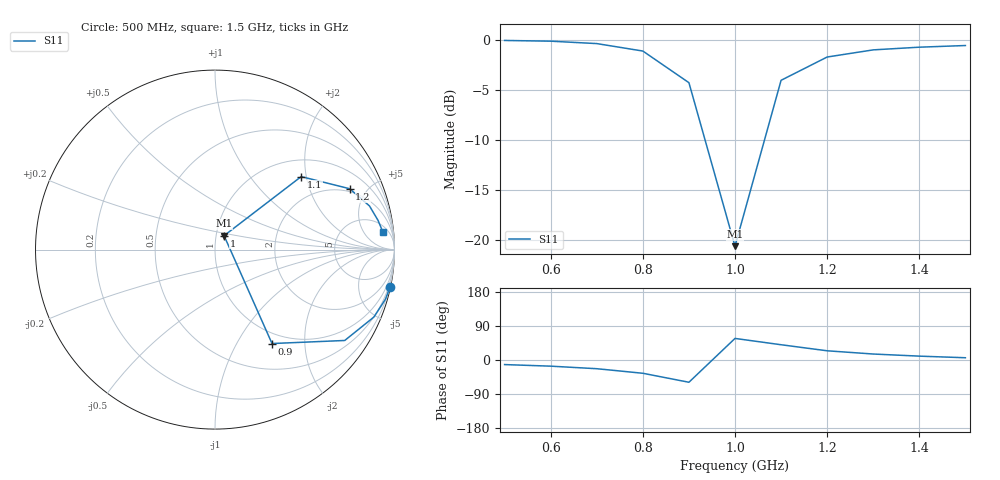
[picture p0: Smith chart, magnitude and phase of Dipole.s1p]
! Generated by circuitRF - EM: openEMS
! circuitRF-EM setup: Dipole OwnGrid
! circuitRF-EM layout: Dipole.c3d
! circuitRF-EM written: 2026-10-18 17:09:39Z
! circuitRF-EM geometry: 13da605dc7726f4f
! circuitRF-EM mesh: d696a9e25d07986c
! circuitRF-EM ports: b2d3c631ea696268
! circuitRF-EM model: openEMS 0.37.0 (v0.37.0, CSXCAD v0.7.0)
! circuitRF-EM port 1: 'port/1' from 'armLo' to 'armHi', lumped, 50 Ohm
! circuitRF-EM 3D grid: 132 x 121 x 124 = 1980528 cells; smallest cell 200 um on x, set by 'armLo' edge at x = -100 um; 'armHi' edge at x = -100 um; 'port/1' port extent at x = -100 um; 'armLo' edge at x = 100 um; 'armHi' edge at x = 100 um; 'port/1' port extent at x = 100 um
! circuitRF-EM 3D openEMS run port 1: dt 6.04404E-13 s (estimate 6.61395E-13 s), 17399 steps, port signals unmeasured (stopped within the pulse) and energy 40.2 dB against 40 dB, stopped by openEMS's energy criterion, converged
! circuitRF-EM 3D dielectric loss fitted at: 1 GHz
! circuitRF-EM 3D perfect conductors: armLo, armHi
! circuitRF-EM 3D operating temperature: 20 C
! circuitRF-EM: re-running the EM setup rewrites this file. If circuitRF reports it as stale, the layout's cross-section changed after this file was written.
# GHz S RI R 50
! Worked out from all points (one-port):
!   11 points, 500 MHz to 1.5 GHz, reference 50 ohm
!   lowest |S11| = -20.7 dB at 1 GHz (marker M1), VSWR 1.20, Z = 54.6 + j8.55 ohm
!   |S11| at or under -10 dB: 935 MHz to 1.064 GHz (129.1 MHz wide, 12.9 % of centre)
!   S11 on the Smith chart (normalised r, x): 500 MHz: 0.12, -9.44; 900 MHz: 0.85, -1.42; 1 GHz: 1.09, +0.17; 1.1 GHz: 1.39, +1.87; 1.2 GHz: 1.82, +3.83; 1.5 GHz: 8, +14
0.5  0.9752 -0.2089
0.6  0.9495 -0.2767
0.7  0.8855 -0.3756
0.8  0.7228 -0.5063
0.9  0.3177 -0.5233
1  0.0505 0.0776
1.1  0.4802 0.4068
1.2  0.7506 0.339
1.3  0.8608 0.2431
1.4  0.9081 0.1632
1.5  0.9355 0.0976
